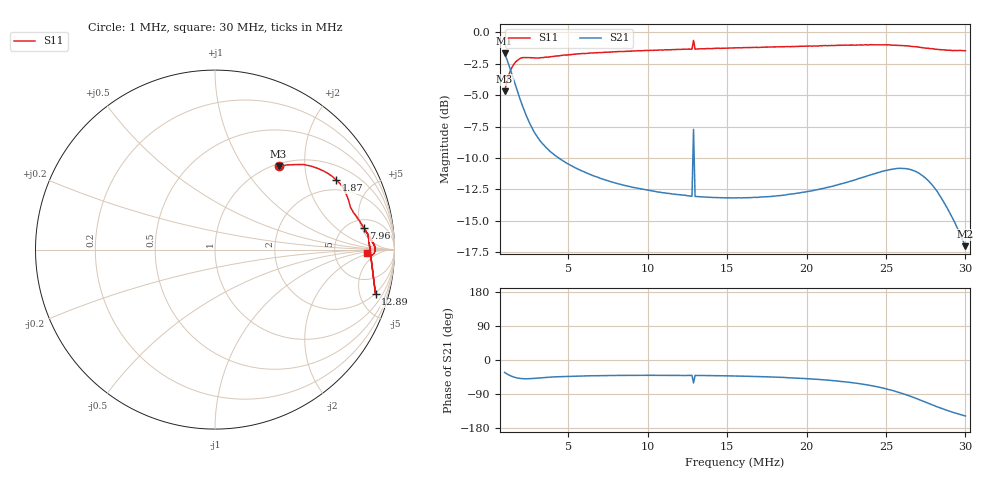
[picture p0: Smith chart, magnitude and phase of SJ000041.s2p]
!File created by NanoVNA-F V2
# Hz S RI R 50
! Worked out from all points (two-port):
!   301 points, 1 MHz to 30 MHz, reference 50 ohm
!   highest |S21| = -1.68 dB at 1 MHz (marker M1); lowest = -17.0 dB at 30 MHz (marker M2)
!   |S21| within 3 dB of the highest: start of sweep to 1.806 MHz
!   lowest |S11| = -4.7 dB at 1 MHz (marker M3), VSWR 3.80, Z = 52.3 + j73.4 ohm
!   |S11| at or under -10 dB: nowhere
!   S12 and S22 are empty: the file has one direction only
!   S11 on the Smith chart (normalised r, x): 1 MHz: 1.05, +1.47; 1.87 MHz: 1.54, +3.03; 7.96 MHz: 6.77, +5.49; 12.89 MHz: 1.88, -6.80; 30 MHz: 12, -1
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1000000  0.3544 0.4632  0.6915 -0.448  0 0  0 0
1289998  0.4924 0.474  0.5632 -0.4716  0 0  0 0
1483330  0.5711 0.453  0.4879 -0.4643  0 0  0 0
1869994  0.6752 0.3881  0.3798 -0.4211  0 0  0 0
2159992  0.7192 0.3352  0.328 -0.3815  0 0  0 0
2546656  0.7426 0.2802  0.2851 -0.3333  0 0  0 0
3319984  0.7602 0.2271  0.2493 -0.2659  0 0  0 0
4383310  0.7833 0.1896  0.2272 -0.2206  0 0  0 0
5833300  0.808 0.1552  0.2085 -0.1889  0 0  0 0
7959952  0.8282 0.1214  0.1905 -0.1641  0 0  0 0
1.06666e7  0.8444 0.0956  0.176 -0.1503  0 0  0 0
1.279325e7  0.8537 0.0803  0.1689 -0.1453  0 0  0 0
1.288992e7  0.8944 -0.2494  0.2021 -0.3581  0 0  0 0
1.298658e7  0.8537 0.0794  0.1685 -0.145  0 0  0 0
1.54999e7  0.8659 0.0633  0.1623 -0.1477  0 0  0 0
2.03332e7  0.88 0.035  0.1501 -0.1796  0 0  0 0
2.323318e7  0.8909 0.0131  0.1234 -0.2303  0 0  0 0
2.51665e7  0.8923 -0.00989  0.0604 -0.2772  0 0  0 0
2.651982e7  0.8808 -0.0265  -0.0264 -0.2834  0 0  0 0
2.767982e7  0.8635 -0.0336  -0.1056 -0.2335  0 0  0 0
2.874314e7  0.8498 -0.0266  -0.1361 -0.1541  0 0  0 0
2.99998e7  0.8453 -0.0162  -0.1192 -0.0753  0 0  0 0
